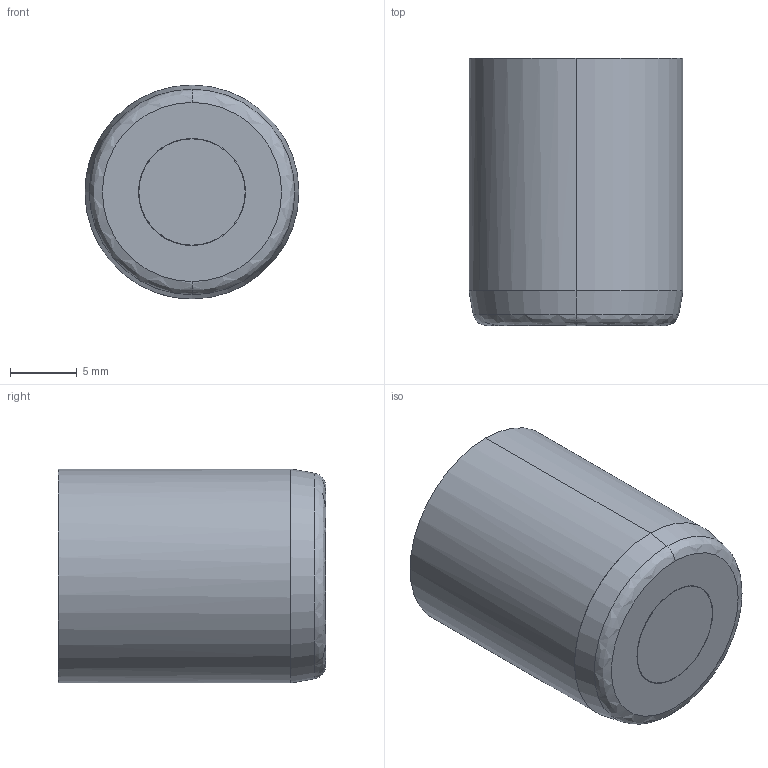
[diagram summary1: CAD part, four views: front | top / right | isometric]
IGES file: header records copied from the file, then geometry measured from it (millimetres).
Start section: START RECORD GO HERE.
Global section: file name: fa168700.igs; native system: DASSAULT SYSTEMES CATIA V5 R20 - www.3ds.com; preprocessor: CATIA Version 5 Release 20 ; author: Utente; organization: NB04-ASUS; date: 20201108.083537; units: millimetre
Bounding box: 16 x 20 x 16 mm (x, y, z)
Surface area: 2684.9 mm2 (no closed solid volume)
Topology: 0 solids, 0 shells, 183 faces, 824 edges, 822 vertices
Faces by surface type: revolution 76, bspline 70, plane 37
